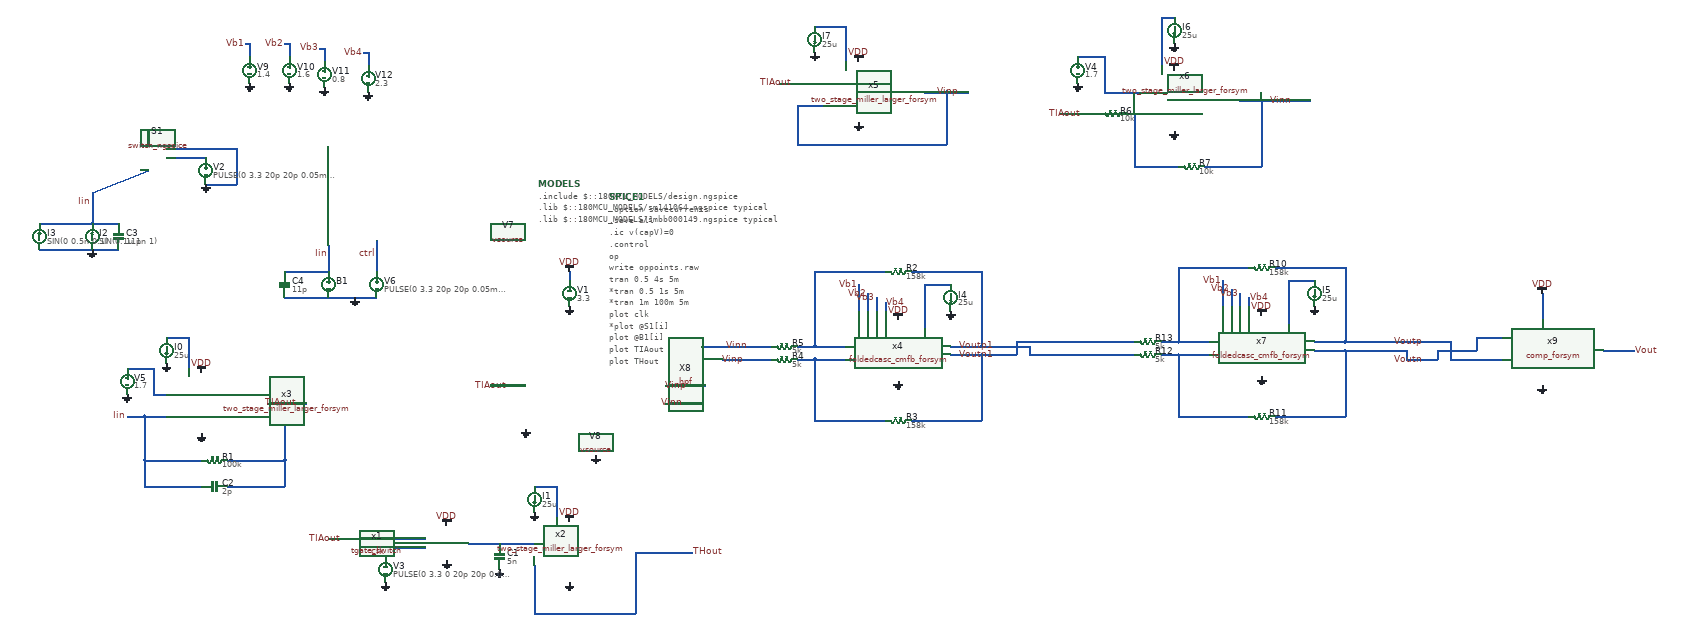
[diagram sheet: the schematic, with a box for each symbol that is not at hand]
v {xschem version=3.4.8RC file_version=1.3}
G {}
K {}
V {}
S {}
F {}
E {}
N 820 -250 890 -250 {lab=#net1
spice_ignore=true}
N 890 -250 970 -250 {lab=#net1
spice_ignore=true}
N 970 -200 970 -90 {lab=THout
spice_ignore=true}
N 1200 -230 1200 -90 {lab=THout
spice_ignore=true}
N 970 -90 1200 -90 {lab=THout
spice_ignore=true}
N 630 -260 720 -260 {lab=TIAout
spice_ignore=true}
N 630 -240 720 -240 {lab=clk
spice_ignore=true}
N 1050 -870 1050 -850 {lab=VDD}
N 630 -240 630 -220 {lab=clk
spice_ignore=true}
N 500 -260 630 -260 {lab=TIAout
spice_ignore=true}
N 360 -570 400 -570 {lab=TIAout
}
N 130 -720 180 -720 {lab=#net1
}
N 180 -720 180 -650 {lab=#net1
}
N 400 -570 400 -440 {lab=TIAout
}
N 80 -540 80 -440 {lab=Iin
}
N 80 -540 130 -540 {lab=Iin
}
N 270 -440 400 -440 {lab=TIAout
}
N 80 -440 210 -440 {lab=Iin
}
N 270 -380 400 -380 {lab=TIAout
}
N 400 -440 400 -380 {lab=TIAout
}
N 80 -380 210 -380 {lab=Iin
}
N 80 -440 80 -380 {lab=Iin
}
N 400 -570 450 -570 {lab=TIAout
}
N 40 -540 80 -540 {lab=Iin
}
N 40 -650 100 -650 {lab=#net2
}
N 100 -650 100 -590 {lab=#net2
}
N 100 -590 130 -590 {lab=#net2
}
N -40 -1010 -40 -980 {lab=Iin
}
N -40 -980 20 -980 {lab=Iin
}
N -40 -920 20 -920 {lab=0
}
N 1200 -230 1330 -230 {lab=THout
spice_ignore=true}
N 970 -380 1020 -380 {lab=#net4
spice_ignore=true}
N 1020 -380 1020 -310 {lab=#net4
spice_ignore=true}
N -40 -1050 -40 -1010 {lab=Iin
}
N 130 -1130 220 -1130 {lab=#net3
}
N 130 -1150 290 -1150 {lab=0
}
N 220 -1070 290 -1070 {lab=0
}
N 290 -1150 290 -1070 {lab=0
}
N -160 -980 -40 -980 {lab=Iin
}
N -160 -920 -40 -920 {lab=0
}
N -40 -1050 90 -1100 {lab=Iin
}
N 90 -1190 90 -1160 {lab=#net4
}
N 1920 -680 1990 -680 {lab=Voutn1
}
N 1990 -680 1990 -530 {lab=Voutn1
}
N 1610 -670 1680 -670 {lab=#net5
}
N 1610 -700 1680 -700 {lab=#net6
}
N 1610 -870 1610 -720 {lab=#net6
}
N 1920 -700 1990 -700 {lab=Voutp1
}
N 1990 -870 1990 -700 {lab=Voutp1
}
N 1990 -700 2100 -700 {lab=Voutp1
}
N 1990 -680 2070 -680 {lab=Voutn1
}
N 1710 -840 1710 -780 {lab=Vb1
}
N 1730 -820 1730 -780 {lab=Vb2
}
N 1830 -870 1990 -870 {lab=Voutp1
}
N 1610 -870 1770 -870 {lab=#net6
}
N 1830 -530 1990 -530 {lab=Voutn1
}
N 1610 -530 1770 -530 {lab=#net5
}
N 1570 -700 1610 -700 {lab=#net6
}
N 1570 -670 1610 -670 {lab=#net5
}
N 1610 -720 1610 -700 {lab=#net6
}
N 1610 -670 1610 -530 {lab=#net5
}
N 1750 -810 1750 -780 {lab=Vb3
}
N 1770 -800 1770 -780 {lab=Vb4
}
N 1860 -840 1860 -740 {lab=#net7
}
N 1860 -840 1920 -840 {lab=#net7
}
N 2100 -700 2100 -680 {lab=Voutp1
}
N 2100 -680 2220 -680 {lab=Voutp1
}
N 2070 -710 2220 -710 {lab=Voutn1
}
N 2070 -710 2070 -680 {lab=Voutn1
}
N 2750 -690 2820 -690 {lab=Voutn
}
N 2820 -690 2820 -540 {lab=Voutn
}
N 2440 -680 2510 -680 {lab=#net8
}
N 2440 -710 2510 -710 {lab=#net9
}
N 2440 -880 2440 -730 {lab=#net9
}
N 2750 -710 2820 -710 {lab=Voutp
}
N 2820 -880 2820 -710 {lab=Voutp
}
N 2540 -850 2540 -790 {lab=Vb1
}
N 2560 -830 2560 -790 {lab=Vb2
}
N 2660 -880 2820 -880 {lab=Voutp
}
N 2440 -880 2600 -880 {lab=#net9
}
N 2660 -540 2820 -540 {lab=Voutn
}
N 2440 -540 2600 -540 {lab=#net8
}
N 2400 -710 2440 -710 {lab=#net9
}
N 2400 -680 2440 -680 {lab=#net8
}
N 2300 -680 2340 -680 {lab=Voutp1
}
N 2440 -730 2440 -710 {lab=#net9
}
N 2440 -680 2440 -540 {lab=#net8
}
N 2580 -820 2580 -790 {lab=Vb3
}
N 2600 -810 2600 -790 {lab=Vb4
}
N 2690 -850 2690 -750 {lab=#net10
}
N 2690 -850 2750 -850 {lab=#net10
}
N 2300 -710 2340 -710 {lab=Voutn1
}
N 2820 -710 2910 -710 {lab=Voutp
}
N 2820 -690 2910 -690 {lab=Voutn
}
N 2220 -710 2300 -710 {lab=Voutn1
}
N 2220 -680 2300 -680 {lab=Voutp1
}
N 320 -1390 320 -1360 {lab=Vb1
}
N 310 -1390 320 -1390 {lab=Vb1
}
N 410 -1390 410 -1360 {lab=Vb2
}
N 400 -1390 410 -1390 {lab=Vb2
}
N 490 -1380 490 -1350 {lab=Vb3
}
N 480 -1380 490 -1380 {lab=Vb3
}
N 590 -1370 590 -1340 {lab=Vb4
}
N 580 -1370 590 -1370 {lab=Vb4
}
N 1530 -1300 1630 -1300 {lab=TIAout
spice_ignore=true}
N 1570 -1250 1630 -1250 {lab=Vinp
spice_ignore=true}
N 1570 -1250 1570 -1160 {lab=Vinp
spice_ignore=true}
N 1570 -1160 1910 -1160 {lab=Vinp
spice_ignore=true}
N 1910 -1280 1910 -1160 {lab=Vinp
spice_ignore=true}
N 1860 -1280 1910 -1280 {lab=Vinp
spice_ignore=true}
N 2580 -1260 2740 -1260 {lab=Vinn
spice_ignore=true}
N 1610 -1430 1680 -1430 {lab=#net11
spice_ignore=true}
N 1680 -1430 1680 -1350 {lab=#net11
spice_ignore=true}
N 2400 -1450 2400 -1340 {lab=#net12
spice_ignore=true}
N 2400 -1450 2430 -1450 {lab=#net12
spice_ignore=true}
N 1910 -1280 1960 -1280 {lab=Vinp
spice_ignore=true}
N 2310 -1280 2350 -1280 {lab=#net13
spice_ignore=true}
N 2310 -1230 2350 -1230 {lab=#net14
spice_ignore=true}
N 2270 -1280 2310 -1280 {lab=#net13
spice_ignore=true}
N 2630 -1260 2630 -1110 {lab=Vinn
spice_ignore=true}
N 2500 -1110 2630 -1110 {lab=Vinn
spice_ignore=true}
N 2340 -1110 2440 -1110 {lab=#net14
spice_ignore=true}
N 2340 -1230 2340 -1110 {lab=#net14
spice_ignore=true}
N 2170 -1230 2260 -1230 {lab=TIAout
spice_ignore=true}
N 2210 -1360 2270 -1360 {lab=#net13
spice_ignore=true}
N 2270 -1360 2270 -1280 {lab=#net13
spice_ignore=true}
N 1400 -700 1510 -700 {lab=Vinn
}
N 1400 -670 1510 -670 {lab=Vinp
}
N 500 -810 610 -810 {lab=0
spice_ignore=true}
N 610 -940 610 -870 {lab=ctrl
spice_ignore=true}
N 500 -930 500 -870 {lab=Iin
spice_ignore=true}
N 400 -870 500 -870 {lab=Iin
spice_ignore=true}
N 400 -810 500 -810 {lab=0
spice_ignore=true}
N 1350 -700 1400 -700 {lab=Vinn}
N 2910 -710 2960 -710 {lab=Voutp}
N 2910 -690 2960 -690 {lab=Voutn}
N 2960 -690 2960 -670 {lab=Voutn}
N 2960 -710 3030 -710 {lab=Voutp}
N 2960 -670 3030 -670 {lab=Voutn}
N 3270 -820 3270 -760 {lab=VDD}
N 3410 -690 3480 -690 {lab=Vout}
N 3120 -720 3180 -720 {lab=Voutn}
N 3100 -670 3180 -670 {lab=Voutp}
N 3120 -720 3120 -700 {lab=Voutn}
N 3060 -670 3100 -670 {lab=Voutp}
N 3030 -710 3060 -710 {lab=Voutp}
N 3060 -710 3060 -670 {lab=Voutp}
N 3030 -690 3030 -670 {lab=Voutn}
N 3030 -690 3120 -690 {lab=Voutn}
N 3120 -700 3120 -690 {lab=Voutn}
N 870 -610 950 -610 {lab=TIAout}
N 1270 -610 1360 -610 {lab=Vinp}
N 1270 -570 1350 -570 {lab=Vinn}
C {capa.sym} 890 -220 0 0 {name=C1
m=1
value=5n
footprint=1206
device="ceramic capacitor"
spice_ignore=true}
C {gnd.sym} 1050 -160 0 0 {name=l1 lab=0
spice_ignore=true}
C {gnd.sym} 890 -190 0 0 {name=l2 lab=0
spice_ignore=true}
C {gnd.sym} 770 -210 0 0 {name=l3 lab=0
spice_ignore=true}
C {vdd.sym} 1050 -300 0 0 {name=l4 lab=VDD
spice_ignore=true}
C {vdd.sym} 770 -290 0 0 {name=l5 lab=VDD
spice_ignore=true}
C {chipathon-2026-ppg/jz_tia/two_stage_miller_larger_forsym.sym} 1050 -230 0 0 {name=x2
spice_ignore=true}
C {chipathon-2026-ppg/jz_trackhold/tgate_switch.sym} 840 -240 0 0 {name=x1
spice_ignore=true}
C {code.sym} 980 -1070 0 0 {name=MODELS only_toplevel=true  
format="tcleval( @value )" 
value="
.include $::180MCU_MODELS/design.ngspice
.lib $::180MCU_MODELS/sm141064.ngspice typical
.lib $::180MCU_MODELS/smbb000149.ngspice typical
"}
C {vsource.sym} 1050 -820 0 0 {name=V1 value=3.3 savecurrent=false}
C {vdd.sym} 1050 -870 0 0 {name=l6 lab=VDD}
C {gnd.sym} 1050 -790 0 0 {name=l11 lab=0}
C {code_shown.sym} 1140 -1040 0 0 {name=SPICE1 only_toplevel=false value=".option savecurrents
.save all
.ic v(capV)=0
.control
op
write oppoints.raw
tran 0.5 4s 5m
*tran 0.5 1s 5m
*tran 1m 100m 5m
plot clk
*plot @S1[i]
plot @B1[i]
plot TIAout
plot THout
plot Vinp Vinn
plot Voutp1 Voutn1
plot Voutp Voutn
plot Vout
.endc"
}
C {vsource.sym} 630 -190 0 0 {name=V3 value="PULSE(0 3.3 0 20p 20p 0.05m 0.5m)" savecurrent=false
spice_ignore=true}
C {gnd.sym} 630 -160 0 0 {name=l7 lab=0
spice_ignore=true}
C {isource.sym} 130 -690 0 0 {name=I0 value=25u
}
C {gnd.sym} 130 -660 0 0 {name=l9 lab=0
}
C {vdd.sym} 210 -640 0 0 {name=l10 lab=VDD
}
C {gnd.sym} 210 -500 0 0 {name=l12 lab=0
}
C {lab_pin.sym} 40 -540 0 0 {name=p1 sig_type=std_logic lab=Iin
spice_ignore=short}
C {res.sym} 240 -440 1 0 {name=R1
value=100k
footprint=1206
device=resistor
m=1
}
C {capa.sym} 240 -380 1 0 {name=C2
m=1
value=2p
footprint=1206
device="ceramic capacitor"
}
C {gnd.sym} 2210 -1300 0 0 {name=l13 lab=0
spice_ignore=true}
C {vsource.sym} 2210 -1330 0 0 {name=V4 value=1.7 savecurrent=false
spice_ignore=true}
C {chipathon-2026-ppg/jz_tia/two_stage_miller_larger_forsym.sym} 210 -570 0 0 {name=x3
}
C {gnd.sym} -40 -920 0 0 {name=l31 lab=0
}
C {lab_pin.sym} -40 -1030 0 0 {name=p11 sig_type=std_logic lab=Iin
}
C {capa.sym} 20 -950 0 0 {name=C3
m=1
value=11p
footprint=1206
device="ceramic capacitor"
}
C {isource.sym} -40 -950 2 0 {name=I2 value="SIN(0.1u 1n 1)"
}
C {lab_pin.sym} 430 -570 1 0 {name=p2 sig_type=std_logic lab=TIAout
}
C {lab_pin.sym} 1330 -230 2 0 {name=p3 sig_type=std_logic lab=THout
spice_ignore=true}
C {isource.sym} 970 -350 0 0 {name=I1 value=25u
spice_ignore=true}
C {gnd.sym} 970 -320 0 0 {name=l8 lab=0
spice_ignore=true}
C {lab_pin.sym} 630 -230 0 0 {name=p5 sig_type=std_logic lab=clk
spice_ignore=true}
C {vsource.sym} 220 -1100 0 0 {name=V2 value="PULSE(0 3.3 20p 20p 0.05m 0.5m)" savecurrent=false
}
C {gnd.sym} 220 -1070 0 0 {name=l14 lab=0
}
C {isource.sym} -160 -950 2 0 {name=I3 value="SIN(0 0.5n 0.1)"
}
C {switch_ngspice.sym} 90 -1130 2 0 {name=S1 model=SW1
device_model=".MODEL SW1 SW 
+ VT=0.9 VH=0.01
+ RON=1 ROFF=10e6 "
}
C {lab_pin.sym} 1730 -820 3 1 {name=p6 sig_type=std_logic lab=Vb2
}
C {lab_pin.sym} 1710 -840 0 0 {name=p7 sig_type=std_logic lab=Vb1
}
C {vdd.sym} 1800 -760 0 0 {name=l15 lab=VDD
}
C {isource.sym} 1920 -810 0 0 {name=I4 value=25u
}
C {gnd.sym} 1800 -620 0 0 {name=l16 lab=0
}
C {res.sym} 1800 -870 1 0 {name=R2
value=158k
footprint=1206
device=resistor
m=1
}
C {res.sym} 1800 -530 1 0 {name=R3
value=158k
footprint=1206
device=resistor
m=1
}
C {res.sym} 1540 -670 1 0 {name=R4
value=5k
footprint=1206
device=resistor
m=1
}
C {res.sym} 1540 -700 1 0 {name=R5
value=5k
footprint=1206
device=resistor
m=1
}
C {chipathon-2026-ppg/jz_fda2/foldedcasc_cmfb_forsym.sym} 1810 -490 0 0 {name=x4
}
C {lab_pin.sym} 1770 -800 0 1 {name=p8 sig_type=std_logic lab=Vb4
}
C {lab_pin.sym} 1750 -810 3 1 {name=p9 sig_type=std_logic lab=Vb3
}
C {gnd.sym} 1920 -780 0 0 {name=l17 lab=0
}
C {lab_pin.sym} 2560 -830 3 1 {name=p24 sig_type=std_logic lab=Vb2
}
C {lab_pin.sym} 2540 -850 0 0 {name=p25 sig_type=std_logic lab=Vb1
}
C {vdd.sym} 2630 -770 0 0 {name=l24 lab=VDD
}
C {isource.sym} 2750 -820 0 0 {name=I5 value=25u
}
C {gnd.sym} 2630 -630 0 0 {name=l25 lab=0
}
C {res.sym} 2630 -880 1 0 {name=R10
value=158k
footprint=1206
device=resistor
m=1
}
C {res.sym} 2630 -540 1 0 {name=R11
value=158k
footprint=1206
device=resistor
m=1
}
C {res.sym} 2370 -680 1 0 {name=R12
value=5k
footprint=1206
device=resistor
m=1
}
C {res.sym} 2370 -710 1 0 {name=R13
value=5k
footprint=1206
device=resistor
m=1
}
C {chipathon-2026-ppg/jz_fda2/foldedcasc_cmfb_forsym.sym} 2640 -500 0 0 {name=x7
}
C {lab_pin.sym} 2600 -810 0 1 {name=p26 sig_type=std_logic lab=Vb4
}
C {lab_pin.sym} 2580 -820 3 1 {name=p27 sig_type=std_logic lab=Vb3
}
C {gnd.sym} 2750 -790 0 0 {name=l26 lab=0
}
C {vsource.sym} 320 -1330 0 0 {name=V9 value=1.4 savecurrent=false
}
C {gnd.sym} 320 -1300 0 0 {name=l18 lab=0
}
C {lab_pin.sym} 310 -1390 0 0 {name=p14 sig_type=std_logic lab=Vb1
}
C {vsource.sym} 410 -1330 0 0 {name=V10 value=1.6 savecurrent=false
}
C {gnd.sym} 410 -1300 0 0 {name=l19 lab=0
}
C {lab_pin.sym} 400 -1390 0 0 {name=p15 sig_type=std_logic lab=Vb2
}
C {vsource.sym} 490 -1320 0 0 {name=V11 value=0.8 savecurrent=false
}
C {gnd.sym} 490 -1290 0 0 {name=l20 lab=0
}
C {lab_pin.sym} 480 -1380 0 0 {name=p16 sig_type=std_logic lab=Vb3
}
C {vsource.sym} 590 -1310 0 0 {name=V12 value=2.3 savecurrent=false
}
C {gnd.sym} 590 -1280 0 0 {name=l21 lab=0
}
C {lab_pin.sym} 580 -1370 0 0 {name=p17 sig_type=std_logic lab=Vb4
}
C {chipathon-2026-ppg/jz_tia/two_stage_miller_larger_forsym.sym} 1710 -1280 0 0 {name=x5
spice_ignore=true}
C {chipathon-2026-ppg/jz_tia/two_stage_miller_larger_forsym.sym} 2430 -1260 0 0 {name=x6
spice_ignore=true}
C {gnd.sym} 1710 -1210 0 0 {name=l22 lab=0
spice_ignore=true}
C {gnd.sym} 2430 -1190 0 0 {name=l23 lab=0
spice_ignore=true}
C {isource.sym} 2430 -1420 0 0 {name=I6 value=25u
spice_ignore=true}
C {gnd.sym} 2430 -1390 0 0 {name=l27 lab=0
spice_ignore=true}
C {vdd.sym} 1710 -1350 0 0 {name=l28 lab=VDD
spice_ignore=true}
C {vdd.sym} 2430 -1330 0 0 {name=l29 lab=VDD
spice_ignore=true}
C {lab_pin.sym} 1560 -1300 1 0 {name=p10 sig_type=std_logic lab=TIAout
spice_ignore=true}
C {lab_pin.sym} 2700 -1260 1 0 {name=p12 sig_type=std_logic lab=Vinn
spice_ignore=true}
C {lab_pin.sym} 2220 -1230 3 0 {name=p13 sig_type=std_logic lab=TIAout
spice_ignore=true}
C {lab_pin.sym} 1940 -1280 1 0 {name=p18 sig_type=std_logic lab=Vinp
spice_ignore=true}
C {isource.sym} 1610 -1400 0 0 {name=I7 value=25u
spice_ignore=true}
C {gnd.sym} 1610 -1370 0 0 {name=l30 lab=0
spice_ignore=true}
C {res.sym} 2290 -1230 1 0 {name=R6
value=10k
footprint=1206
device=resistor
m=1
spice_ignore=true}
C {res.sym} 2470 -1110 1 0 {name=R7
value=10k
footprint=1206
device=resistor
m=1
spice_ignore=true}
C {lab_pin.sym} 910 -610 1 0 {name=p19 sig_type=std_logic lab=TIAout
}
C {lab_pin.sym} 1460 -700 1 0 {name=p20 sig_type=std_logic lab=Vinn
}
C {lab_pin.sym} 3000 -710 1 0 {name=p21 sig_type=std_logic lab=Voutp
}
C {lab_pin.sym} 3000 -670 3 0 {name=p22 sig_type=std_logic lab=Voutn
}
C {gnd.sym} 40 -590 0 0 {name=l32 lab=0
}
C {vsource.sym} 40 -620 0 0 {name=V5 value=1.7 savecurrent=false
}
C {lab_pin.sym} 530 -260 1 0 {name=p23 sig_type=std_logic lab=TIAout
spice_ignore=true}
C {bsource.sym} 500 -840 0 0 {name=B1 VAR=I FUNC="(0.1u + 1n * sin(2*pi*1*time)) * (v(ctrl) > 1.65 ? 1 : 0)" m=1
spice_ignore=true}
C {vsource.sym} 610 -840 0 0 {name=V6 value="PULSE(0 3.3 20p 20p 0.05m 0.5m)" savecurrent=false
spice_ignore=true}
C {gnd.sym} 560 -810 0 0 {name=l33 lab=0
spice_ignore=true}
C {lab_pin.sym} 500 -910 0 0 {name=p28 sig_type=std_logic lab=Iin
spice_ignore=true}
C {lab_pin.sym} 610 -910 0 0 {name=p29 sig_type=std_logic lab=ctrl
spice_ignore=true}
C {capa.sym} 400 -840 0 0 {name=C4
m=1
value=11p
footprint=1206
device="ceramic capacitor"
spice_ignore=true}
C {gnd.sym} 950 -510 0 0 {name=l34 lab=0
}
C {vsource.sym} 950 -540 0 0 {name=V7 value=1.7 savecurrent=false
}
C {lab_pin.sym} 2020 -700 1 0 {name=p30 sig_type=std_logic lab=Voutp1
}
C {lab_pin.sym} 2020 -680 3 0 {name=p31 sig_type=std_logic lab=Voutn1
}
C {chipathon-2026-ppg/ps-filters/hpf.sym} 1110 -590 0 0 {name=X8}
C {gnd.sym} 1110 -450 0 0 {name=l35 lab=0
}
C {vsource.sym} 1110 -480 0 0 {name=V8 value=1.7 savecurrent=false
}
C {chipathon-2026-ppg/comparator/schematic-design/comp_forsym.sym} 3280 -690 0 0 {name=x9}
C {gnd.sym} 3270 -610 0 0 {name=l36 lab=0
}
C {lab_pin.sym} 3480 -690 0 1 {name=p32 sig_type=std_logic lab=Vout
}
C {vdd.sym} 3270 -820 0 0 {name=l37 lab=VDD}
C {lab_pin.sym} 1320 -610 1 0 {name=p33 sig_type=std_logic lab=Vinp
}
C {lab_pin.sym} 1310 -570 3 0 {name=p34 sig_type=std_logic lab=Vinn
}
C {lab_pin.sym} 1450 -670 3 0 {name=p35 sig_type=std_logic lab=Vinp
}
